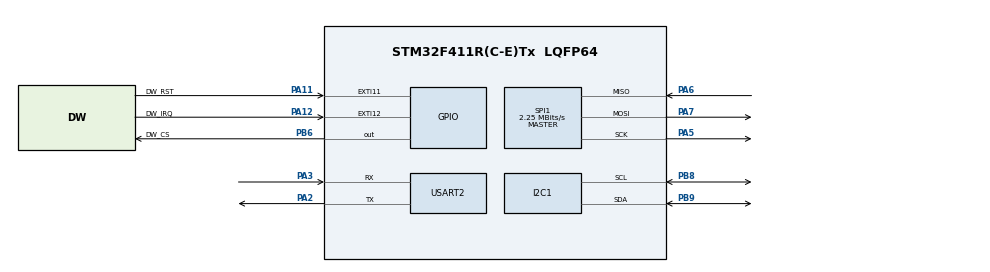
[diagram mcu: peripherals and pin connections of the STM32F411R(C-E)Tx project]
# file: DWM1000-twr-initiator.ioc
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I2C1.I2C_Mode=I2C_Fast
Mcu.Family=STM32F4
Mcu.Name=STM32F411R(C-E)Tx
Mcu.Package=LQFP64
NVIC.EXTI15_10_IRQn=true\:4\:0\:true\:false\:true\:true\:true\:true
NVIC.PriorityGroup=NVIC_PRIORITYGROUP_4
PA11.GPIO_Label=DW_RST
PA11.Signal=GPXTI11
PA12.GPIO_Label=DW_IRQ
PA12.GPIO_PuPd=GPIO_PULLDOWN
PA12.Signal=GPXTI12
PA2.Mode=Asynchronous
PA2.Signal=USART2_TX
PA3.Mode=Asynchronous
PA3.Signal=USART2_RX
PA5.Mode=Full_Duplex_Master
PA5.Signal=SPI1_SCK
PA6.Mode=Full_Duplex_Master
PA6.Signal=SPI1_MISO
PA7.Mode=Full_Duplex_Master
PA7.Signal=SPI1_MOSI
PB6.GPIO_Label=DW_CS
PB6.Signal=GPIO_Output
PB8.Mode=I2C
PB8.Signal=I2C1_SCL
PB9.Mode=I2C
PB9.Signal=I2C1_SDA
PC14-OSC32_IN.Mode=LSE-External-Oscillator
PC14-OSC32_IN.Signal=RCC_OSC32_IN
PC15-OSC32_OUT.Mode=LSE-External-Oscillator
PC15-OSC32_OUT.Signal=RCC_OSC32_OUT
PH0\ -\ OSC_IN.Mode=HSE-External-Oscillator
PH0\ -\ OSC_IN.Signal=RCC_OSC_IN
PH1\ -\ OSC_OUT.Mode=HSE-External-Oscillator
PH1\ -\ OSC_OUT.Signal=RCC_OSC_OUT
ProjectManager.HeapSize=0x200
ProjectManager.StackSize=0x400
ProjectManager.TargetToolchain=STM32CubeIDE
RCC.48MHZClocksFreq_Value=36000000
RCC.AHBFreq_Value=72000000
RCC.APB1CLKDivider=RCC_HCLK_DIV2
RCC.APB1Freq_Value=36000000
RCC.APB1TimFreq_Value=72000000
RCC.APB2Freq_Value=72000000
RCC.APB2TimFreq_Value=72000000
RCC.CortexFreq_Value=72000000
RCC.FLatency-AdvancedSettings=FLASH_LATENCY_2
RCC.HCLKFreq_Value=72000000
RCC.HSE_VALUE=26000000
RCC.HSI_VALUE=16000000
RCC.PLLM=13
RCC.PLLN=72
RCC.PLLSourceVirtual=RCC_PLLSOURCE_HSE
RCC.SYSCLKFreq_VALUE=72000000
RCC.SYSCLKSource=RCC_SYSCLKSOURCE_PLLCLK
RCC.VCOOutputFreq_Value=144000000
SPI1.BaudRatePrescaler=SPI_BAUDRATEPRESCALER_32
SPI1.CalculateBaudRate=2.25 MBits/s
SPI1.Direction=SPI_DIRECTION_2LINES
SPI1.Mode=SPI_MODE_MASTER
SPI1.VirtualType=VM_MASTER
USART2.VirtualMode=VM_ASYNC
board=NUCLEO-F411RE

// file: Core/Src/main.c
/* USER CODE BEGIN Header */
/**
  ******************************************************************************
  * @file           : main.c
  * @brief          : Main program body
  ******************************************************************************
  * @attention
  *
  * Copyright (c) 2023 STMicroelectronics.
  * All rights reserved.
  *
  * This software is licensed under terms that can be found in the LICENSE file
  * in the root directory of this software component.
  * If no LICENSE file comes with this software, it is provided AS-IS.
  *
  ******************************************************************************
  */
/* USER CODE END Header */
#include "main.h"
#include "i2c.h"
#include "spi.h"
#include "usart.h"
#include "gpio.h"

/* USER CODE BEGIN Includes */
#include "port.h"
#include "stm32f4xx_hal.h"
/* USER CODE END Includes */

void SystemClock_Config(void);

/* USER CODE BEGIN 0 */
extern int dw_main(void);
/* USER CODE END 0 */

int main(void)
{

  /* MCU Configuration--------------------------------------------------------*/

  /* Reset of all peripherals, Initializes the Flash interface and the Systick. */
  HAL_Init();

  /* Configure the system clock */
  SystemClock_Config();

  /* Initialize all configured peripherals */
  MX_GPIO_Init();
  MX_USART2_UART_Init();
  MX_I2C1_Init();
  MX_SPI1_Init();
  /* USER CODE BEGIN 2 */
  setup_DW1000RSTnIRQ(0);
  SSD1306_Init();
  dw_main();
  /* USER CODE END 2 */

  /* Infinite loop */
  while (1)
  {

  }
}

void SystemClock_Config(void)
{
  RCC_OscInitTypeDef RCC_OscInitStruct = {0};
  RCC_ClkInitTypeDef RCC_ClkInitStruct = {0};

  /** Configure the main internal regulator output voltage
  */
  __HAL_RCC_PWR_CLK_ENABLE();
  __HAL_PWR_VOLTAGESCALING_CONFIG(PWR_REGULATOR_VOLTAGE_SCALE1);

  /** Initializes the RCC Oscillators according to the specified parameters
  * in the RCC_OscInitTypeDef structure.
  */
  RCC_OscInitStruct.OscillatorType = RCC_OSCILLATORTYPE_HSE;
  RCC_OscInitStruct.HSEState = RCC_HSE_ON;
  RCC_OscInitStruct.PLL.PLLState = RCC_PLL_ON;
  RCC_OscInitStruct.PLL.PLLSource = RCC_PLLSOURCE_HSE;
  RCC_OscInitStruct.PLL.PLLM = 13;
  RCC_OscInitStruct.PLL.PLLN = 100;
  RCC_OscInitStruct.PLL.PLLP = RCC_PLLP_DIV2;
  RCC_OscInitStruct.PLL.PLLQ = 4;
  if (HAL_RCC_OscConfig(&RCC_OscInitStruct) != HAL_OK)
  {
    Error_Handler();
  }

  /** Initializes the CPU, AHB and APB buses clocks
  */
  RCC_ClkInitStruct.ClockType = RCC_CLOCKTYPE_HCLK|RCC_CLOCKTYPE_SYSCLK
                              |RCC_CLOCKTYPE_PCLK1|RCC_CLOCKTYPE_PCLK2;
  RCC_ClkInitStruct.SYSCLKSource = RCC_SYSCLKSOURCE_PLLCLK;
  RCC_ClkInitStruct.AHBCLKDivider = RCC_SYSCLK_DIV1;
  RCC_ClkInitStruct.APB1CLKDivider = RCC_HCLK_DIV2;
  RCC_ClkInitStruct.APB2CLKDivider = RCC_HCLK_DIV1;

  if (HAL_RCC_ClockConfig(&RCC_ClkInitStruct, FLASH_LATENCY_3) != HAL_OK)
  {
    Error_Handler();
  }
}

void Error_Handler(void)
{
  __disable_irq();
  while (1)
  {
  }
}
